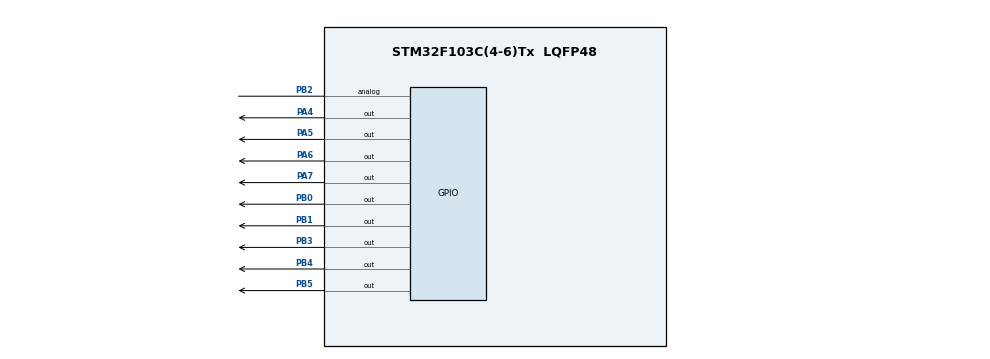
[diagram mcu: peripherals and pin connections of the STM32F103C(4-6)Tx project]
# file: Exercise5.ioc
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Mcu.Family=STM32F1
Mcu.Name=STM32F103C(4-6)Tx
Mcu.Package=LQFP48
NVIC.PriorityGroup=NVIC_PRIORITYGROUP_4
NVIC.TIM2_IRQn=true\:0\:0\:false\:false\:true\:true\:true
PA4.Signal=GPIO_Output
PA5.Signal=GPIO_Output
PA6.Signal=GPIO_Output
PA7.Signal=GPIO_Output
PB0.Signal=GPIO_Output
PB1.Signal=GPIO_Output
PB2.Signal=GPIO_Analog
PB3.Signal=GPIO_Output
PB4.Signal=GPIO_Output
PB5.Signal=GPIO_Output
ProjectManager.HeapSize=0x200
ProjectManager.StackSize=0x400
ProjectManager.TargetToolchain=STM32CubeIDE
RCC.APB1Freq_Value=8000000
RCC.APB2Freq_Value=8000000
TIM2.Period=9
TIM2.Prescaler=7999
VP_SYS_VS_ND.Mode=No_Debug
VP_TIM2_VS_ClockSourceINT.Mode=Internal
board=custom

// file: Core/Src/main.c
/* USER CODE BEGIN Header */
/**
  ******************************************************************************
  * @file           : main.c
  * @brief          : Main program body
  ******************************************************************************
  * @attention
  *
  * <h2><center>&copy; Copyright (c) 2021 STMicroelectronics.
  * All rights reserved.</center></h2>
  *
  * This software component is licensed by ST under BSD 3-Clause license,
  * the "License"; You may not use this file except in compliance with the
  * License. You may obtain a copy of the License at:
  *                        opensource.org/licenses/BSD-3-Clause
  *
  ******************************************************************************
  */
/* USER CODE END Header */
#include "main.h"

TIM_HandleTypeDef htim2;

void SystemClock_Config(void);
static void MX_GPIO_Init(void);
static void MX_TIM2_Init(void);

int main(void)
{

  /* MCU Configuration--------------------------------------------------------*/

  /* Reset of all peripherals, Initializes the Flash interface and the Systick. */
  HAL_Init();

  /* Configure the system clock */
  SystemClock_Config();

  /* Initialize all configured peripherals */
  MX_GPIO_Init();
  MX_TIM2_Init();
  /* USER CODE BEGIN 2 */
  HAL_TIM_Base_Start_IT (& htim2 );
  /* USER CODE END 2 */

  /* Infinite loop */
  /* USER CODE BEGIN WHILE */
  int hour = 15, minute = 8, second = 1;
  while (1)
  {
    /* USER CODE END WHILE */
	  second ++;
	  if ( second >= 5) {
		  second = 0;
		  minute ++;
	  }
	  if( minute >= 60) {
		   minute = 0;
		   hour ++;
	  }
	  if( hour >=24){
		  hour = 0;
	  }
	  updateClockBuffer (hour,minute);
	  HAL_Delay (1000) ;
  }
}

void SystemClock_Config(void)
{
  RCC_OscInitTypeDef RCC_OscInitStruct = {0};
  RCC_ClkInitTypeDef RCC_ClkInitStruct = {0};

  /** Initializes the RCC Oscillators according to the specified parameters
  * in the RCC_OscInitTypeDef structure.
  */
  RCC_OscInitStruct.OscillatorType = RCC_OSCILLATORTYPE_HSI;
  RCC_OscInitStruct.HSIState = RCC_HSI_ON;
  RCC_OscInitStruct.HSICalibrationValue = RCC_HSICALIBRATION_DEFAULT;
  RCC_OscInitStruct.PLL.PLLState = RCC_PLL_NONE;
  if (HAL_RCC_OscConfig(&RCC_OscInitStruct) != HAL_OK)
  {
    Error_Handler();
  }
  /** Initializes the CPU, AHB and APB buses clocks
  */
  RCC_ClkInitStruct.ClockType = RCC_CLOCKTYPE_HCLK|RCC_CLOCKTYPE_SYSCLK
                              |RCC_CLOCKTYPE_PCLK1|RCC_CLOCKTYPE_PCLK2;
  RCC_ClkInitStruct.SYSCLKSource = RCC_SYSCLKSOURCE_HSI;
  RCC_ClkInitStruct.AHBCLKDivider = RCC_SYSCLK_DIV1;
  RCC_ClkInitStruct.APB1CLKDivider = RCC_HCLK_DIV1;
  RCC_ClkInitStruct.APB2CLKDivider = RCC_HCLK_DIV1;

  if (HAL_RCC_ClockConfig(&RCC_ClkInitStruct, FLASH_LATENCY_0) != HAL_OK)
  {
    Error_Handler();
  }
}

static void MX_TIM2_Init(void)
{

  TIM_ClockConfigTypeDef sClockSourceConfig = {0};
  TIM_MasterConfigTypeDef sMasterConfig = {0};

  htim2.Instance = TIM2;
  htim2.Init.Prescaler = 7999;
  htim2.Init.CounterMode = TIM_COUNTERMODE_UP;
  htim2.Init.Period = 9;
  htim2.Init.ClockDivision = TIM_CLOCKDIVISION_DIV1;
  htim2.Init.AutoReloadPreload = TIM_AUTORELOAD_PRELOAD_DISABLE;
  if (HAL_TIM_Base_Init(&htim2) != HAL_OK)
  {
    Error_Handler();
  }
  sClockSourceConfig.ClockSource = TIM_CLOCKSOURCE_INTERNAL;
  if (HAL_TIM_ConfigClockSource(&htim2, &sClockSourceConfig) != HAL_OK)
  {
    Error_Handler();
  }
  sMasterConfig.MasterOutputTrigger = TIM_TRGO_RESET;
  sMasterConfig.MasterSlaveMode = TIM_MASTERSLAVEMODE_DISABLE;
  if (HAL_TIMEx_MasterConfigSynchronization(&htim2, &sMasterConfig) != HAL_OK)
  {
    Error_Handler();
  }

}

static void MX_GPIO_Init(void)
{
  GPIO_InitTypeDef GPIO_InitStruct = {0};

  /* GPIO Ports Clock Enable */
  __HAL_RCC_GPIOA_CLK_ENABLE();
  __HAL_RCC_GPIOB_CLK_ENABLE();

  /*Configure GPIO pin Output Level */
  HAL_GPIO_WritePin(GPIOA, GPIO_PIN_4|GPIO_PIN_5|GPIO_PIN_6|GPIO_PIN_7
                          |GPIO_PIN_8|GPIO_PIN_9, GPIO_PIN_SET);

  /*Configure GPIO pin Output Level */
  HAL_GPIO_WritePin(GPIOB, GPIO_PIN_0|GPIO_PIN_1|GPIO_PIN_2|GPIO_PIN_3
                          |GPIO_PIN_4|GPIO_PIN_5|GPIO_PIN_6, GPIO_PIN_SET);

  /*Configure GPIO pins : PA4 PA5 PA6 PA7
                           PA8 PA9 */
  GPIO_InitStruct.Pin = GPIO_PIN_4|GPIO_PIN_5|GPIO_PIN_6|GPIO_PIN_7
                          |GPIO_PIN_8|GPIO_PIN_9;
  GPIO_InitStruct.Mode = GPIO_MODE_OUTPUT_PP;
  GPIO_InitStruct.Pull = GPIO_NOPULL;
  GPIO_InitStruct.Speed = GPIO_SPEED_FREQ_LOW;
  HAL_GPIO_Init(GPIOA, &GPIO_InitStruct);

  /*Configure GPIO pins : PB0 PB1 PB2 PB3
                           PB4 PB5 PB6 */
  GPIO_InitStruct.Pin = GPIO_PIN_0|GPIO_PIN_1|GPIO_PIN_2|GPIO_PIN_3
                          |GPIO_PIN_4|GPIO_PIN_5|GPIO_PIN_6;
  GPIO_InitStruct.Mode = GPIO_MODE_OUTPUT_PP;
  GPIO_InitStruct.Pull = GPIO_NOPULL;
  GPIO_InitStruct.Speed = GPIO_SPEED_FREQ_LOW;
  HAL_GPIO_Init(GPIOB, &GPIO_InitStruct);

}

/* USER CODE BEGIN 4 */

int counter = 100;
void HAL_TIM_PeriodElapsedCallback ( TIM_HandleTypeDef * htim ){
	counter--;
	if( counter == 99) {

		HAL_GPIO_TogglePin(GPIOA,GPIO_PIN_4|GPIO_PIN_5);

		HAL_GPIO_WritePin(GPIOA, GPIO_PIN_6, 0);
		HAL_GPIO_WritePin(GPIOA, GPIO_PIN_7|GPIO_PIN_8|GPIO_PIN_9, 1);
		update7SEG(0);
	}
	if ( counter==75) {
		HAL_GPIO_WritePin(GPIOA, GPIO_PIN_7, 0);
		HAL_GPIO_WritePin(GPIOA, GPIO_PIN_6|GPIO_PIN_8|GPIO_PIN_9, 1);
		update7SEG(1);
	}

	if (counter==50){
		HAL_GPIO_WritePin(GPIOA,GPIO_PIN_8, 0);
		HAL_GPIO_WritePin(GPIOA, GPIO_PIN_6|GPIO_PIN_7|GPIO_PIN_9, 1);
		update7SEG(2);
	}
	if ( counter==25){
		HAL_GPIO_WritePin(GPIOA, GPIO_PIN_9, 0);
		HAL_GPIO_WritePin(GPIOA, GPIO_PIN_6|GPIO_PIN_7|GPIO_PIN_8, 1);
		update7SEG(3);
	}
	if (counter <=0 ){
		counter=100;
	}
}
void display7SEG(int num){
	if ( num==0 ) {
		HAL_GPIO_WritePin(GPIOB, GPIO_PIN_0|GPIO_PIN_1|GPIO_PIN_2|GPIO_PIN_3|GPIO_PIN_4|GPIO_PIN_5,0 );
		HAL_GPIO_WritePin(GPIOB, GPIO_PIN_6,1 );
	}
	if ( num==1 ) {
		HAL_GPIO_WritePin(GPIOB, GPIO_PIN_0|GPIO_PIN_3|GPIO_PIN_4|GPIO_PIN_5|GPIO_PIN_6, 1 );
		HAL_GPIO_WritePin(GPIOB, GPIO_PIN_1|GPIO_PIN_2, 0 );
	}
	if ( num==2 ) {
		HAL_GPIO_WritePin(GPIOB, GPIO_PIN_0|GPIO_PIN_1|GPIO_PIN_3|GPIO_PIN_4|GPIO_PIN_6,0 );
		HAL_GPIO_WritePin(GPIOB, GPIO_PIN_2|GPIO_PIN_5,1 );
	}
	if ( num==3 ) {
		HAL_GPIO_WritePin(GPIOB, GPIO_PIN_0|GPIO_PIN_1|GPIO_PIN_2|GPIO_PIN_3|GPIO_PIN_6,0 );
		HAL_GPIO_WritePin(GPIOB, GPIO_PIN_4|GPIO_PIN_5,1 );
	}
	if ( num==4 ) {
		HAL_GPIO_WritePin(GPIOB, GPIO_PIN_1|GPIO_PIN_2|GPIO_PIN_5|GPIO_PIN_6,0 );
		HAL_GPIO_WritePin(GPIOB, GPIO_PIN_0|GPIO_PIN_3|GPIO_PIN_4,1 );
	}
	if ( num==5 ) {
		HAL_GPIO_WritePin(GPIOB, GPIO_PIN_0|GPIO_PIN_2|GPIO_PIN_3|GPIO_PIN_5|GPIO_PIN_6,0 );
		HAL_GPIO_WritePin(GPIOB, GPIO_PIN_1|GPIO_PIN_4,1);
	}
	if ( num==6 ) {
		HAL_GPIO_WritePin(GPIOB, GPIO_PIN_0|GPIO_PIN_2|GPIO_PIN_3|GPIO_PIN_4|GPIO_PIN_5|GPIO_PIN_6,0 );
		HAL_GPIO_WritePin(GPIOB, GPIO_PIN_1,1 );
	}
	if ( num==7 ) {
		HAL_GPIO_WritePin(GPIOB, GPIO_PIN_0|GPIO_PIN_1|GPIO_PIN_2,0 );
		HAL_GPIO_WritePin(GPIOB, GPIO_PIN_3|GPIO_PIN_4|GPIO_PIN_5|GPIO_PIN_6,1 );
	}
	if ( num==8 ) {
		HAL_GPIO_WritePin(GPIOB, GPIO_PIN_0|GPIO_PIN_1|GPIO_PIN_2|GPIO_PIN_3|GPIO_PIN_4|GPIO_PIN_5|GPIO_PIN_6,0 );
	}
	if ( num==9 ) {
		HAL_GPIO_WritePin(GPIOB, GPIO_PIN_0|GPIO_PIN_1|GPIO_PIN_2|GPIO_PIN_3|GPIO_PIN_5|GPIO_PIN_6,0 );
		HAL_GPIO_WritePin(GPIOB, GPIO_PIN_4,1 );
	}
}

const int MAX_LED = 4;
int index_led = 0;
int led_buffer [4] = {1, 2, 3, 0};
void update7SEG ( int index ){
	 switch ( index ){
	 case 0:
	 // Display the first 7 SEG with led_buffer [0]
		 display7SEG(led_buffer[0]);
	 break ;
	 case 1:
	 // Display the second 7 SEG with led_buffer [1]
		 display7SEG(led_buffer[1]);
	 break ;
	 case 2:
	 // Display the third 7 SEG with led_buffer [2]
		 display7SEG(led_buffer[2]);
	 break ;
	 case 3:
	 // Display the forth 7 SEG with led_buffer [3]
		 display7SEG(led_buffer[3]);
	 break ;

	 default:
	 	 break ;
 }
}

void updateClockBuffer(int h, int m){
	led_buffer[0]=h/10;
	led_buffer[1]=h%10;
	led_buffer[2]=m/10;
	led_buffer[3]=m%10;
}

/* USER CODE END 4 */

void Error_Handler(void)
{
  __disable_irq();
  while (1)
  {
  }
}

/************************ (C) COPYRIGHT STMicroelectronics *****END OF FILE****/
